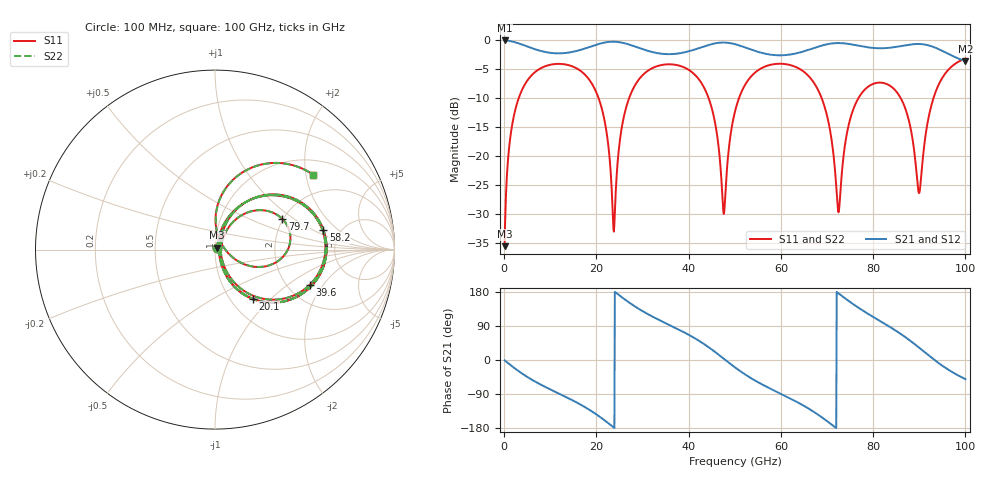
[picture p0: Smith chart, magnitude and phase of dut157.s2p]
! Touchstone file exported from HFSS 2026.1.0
!  File:  C:/ffzhzh/LocalFiles/Ansys_Project_Files/temp_test_TSV_RDL_157_1783465198_7600.aedt
!  Generated:  07:10:39 AM Jul  8, 2026
!  Design:  TSV_RDL
!  Project:  temp_test_TSV_RDL_157_1783465198_7600
! Variables:
!  h_bsmrdl = 4.88um
!  h_ox = 20um
!  h_rdl = 5um
!  h_sub = 64.53um
!  h_tmrdl = 3.89um
!  h_tsv = 64.53um
!  h_via = 3um
!  l_bsmrdl = 234.29um
!  l_sub = 2587.05um
!  l_tmrdl = 346.85um
!  m_sub = 200um
!  pitch = 59.56um
!  r_tsv = 9.57um
!  s_tmrdl = 10um
!  w_bsmrdl = 10.74um
!  w_sub = 500um
!  w_tmrdl = 21.52um
!  x_tsv_center1 = 357.61um
!  x_tsv_center2 = 602.64um
!  x_tsv_center3 = 971.01um
!  x_tsv_center4 = 1216.04um
!  x_tsv_center5 = 1584.41um
!  x_tsv_center6 = 1829.44um
# GHz S MA R 50.000000
! Terminal data exported
! Port[1] = TM_RDL1_1_T1
! Port[2] = TM_RDL5_1_T1
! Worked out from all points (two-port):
!   1000 points, 100 MHz to 100 GHz, reference 50 ohm
!   highest |S21| = -0.11 dB at 100 MHz (marker M1); lowest = -3.7 dB at 100 GHz (marker M2)
!   |S21| within 3 dB of the highest: start of sweep to 98.13 GHz
!   lowest |S11| = -35.6 dB at 100 MHz (marker M3), VSWR 1.03, Z = 51.2 + j1.15 ohm
!   |S11| at or under -10 dB: 20.45 GHz to 27.12 GHz (6.67 GHz wide, 28 % of centre); 68.81 GHz to 76.85 GHz (8.043 GHz wide, 11 % of centre); 85.94 GHz to 93.1 GHz (7.164 GHz wide, 8 % of centre) (the widest 3 of 5)
!   |S22| runs from -35.6 to -3.2 dB; largest |S21 - S12| = 7.7e-14
!   S11 on the Smith chart (normalised r, x): 100 MHz: 1.02, +0.02; 20.1 GHz: 1.26, -0.78; 39.6 GHz: 2.63, -1.50; 58.2 GHz: 3.69, +1.31; 79.7 GHz: 1.97, +0.82; 100 GHz: 1.39, +2.20
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0.1  0.01661 42.7  0.9879 -1.0  0.9879 -1.0  0.01661 42.7
! Gamma 0 0 0 0
! Port Impedance 50 0 50 0
1.5  0.161 70.1  0.972 -14.5  0.972 -14.5  0.161 70.1
4.1  0.386 49.8  0.9041 -37.5  0.9041 -37.5  0.386 49.8
16.8  0.5311 -29.2  0.825 -119.2  0.825 -119.2  0.5311 -29.2
20.1  0.3435 -52.5  0.911 -144.4  0.911 -144.4  0.3435 -52.5
23.8  0.02216 9.0  0.9637 -178.2  0.9637 -178.2  0.02221 8.9
26.7  0.2823 60.1  0.9204 155.1  0.9204 155.1  0.2823 60.1
33.4  0.5969 15.5  0.766 106.8  0.766 106.8  0.5969 15.5
39.6  0.5637 -20.2  0.7887 69.3  0.7887 69.3  0.5637 -20.2
44.9  0.267 -56.0  0.9169 28.7  0.9169 28.7  0.267 -56.0
47.6  0.03148 -1.7  0.9478 3.5  0.9478 3.5  0.03171 -1.7
50.1  0.2454 62.5  0.9163 -19.9  0.9163 -19.9  0.2454 62.4
58.2  0.6143 10.4  0.7414 -78.6  0.7414 -78.6  0.6143 10.3
66.7  0.4521 -40.8  0.8381 -133.4  0.8381 -133.4  0.4521 -40.9
70.2  0.2051 -64.3  0.9191 -163.0  0.9191 -163.0  0.205 -64.6
72.5  0.03252 -1.5  0.938 175.7  0.938 175.7  0.03151 -1.6
75.1  0.2128 54.7  0.9165 152.3  0.9165 152.3  0.2125 54.9
79.7  0.4119 24.6  0.8536 115.9  0.8536 115.9  0.4118 24.7
83.4  0.4076 0.5  0.853 89.0  0.853 89.0  0.4075 0.6
90  0.04777 35.7  0.921 32.1  0.921 32.1  0.04867 35.7
93.5  0.3518 79.7  0.8551 -1.9  0.8551 -1.9  0.3519 79.6
100  0.6879 37.4  0.6556 -50.5  0.6556 -50.5  0.6879 37.3
